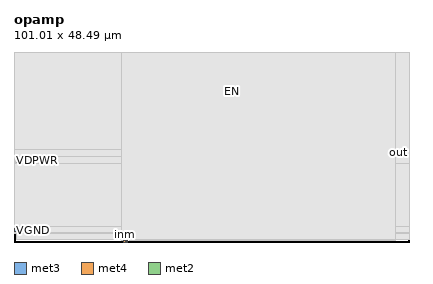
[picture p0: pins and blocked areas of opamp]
MACRO opamp
  CLASS BLOCK ;
  FOREIGN opamp ;
  ORIGIN -78.690 -6.220 ;
  SIZE 101.010 BY 48.490 ;
  PIN VDPWR
    ANTENNAGATEAREA 8.000000 ;
    ANTENNADIFFAREA 205.038895 ;
    PORT
      LAYER met3 ;
        RECT 79.430 26.585 80.430 27.585 ;
    END
  END VDPWR
  PIN inp
    ANTENNAGATEAREA 126.399994 ;
    PORT
      LAYER met4 ;
        RECT 107.350 6.220 107.650 6.520 ;
    END
  END inp
  PIN inm
    ANTENNAGATEAREA 126.399994 ;
    PORT
      LAYER met4 ;
        RECT 106.745 6.220 107.045 6.520 ;
    END
  END inm
  PIN EN
    ANTENNAGATEAREA 0.436500 ;
    PORT
      LAYER met2 ;
        RECT 134.050 44.600 134.350 44.900 ;
    END
  END EN
  PIN VGND
    USE GROUND ;
    PORT
      LAYER met3 ;
        RECT 78.690 8.780 79.255 9.780 ;
    END
  END VGND
  PIN out
    ANTENNADIFFAREA 18.559999 ;
    PORT
      LAYER met3 ;
        RECT 177.595 28.510 178.595 29.510 ;
    END
  END out
  OBS
      LAYER nwell ;
        RECT 79.610 6.770 179.510 54.395 ;
      LAYER li1 ;
        RECT 79.795 6.945 179.330 54.215 ;
      LAYER met1 ;
        RECT 79.605 6.770 179.680 54.365 ;
      LAYER met2 ;
        RECT 79.255 45.180 179.605 54.550 ;
        RECT 79.255 44.320 133.770 45.180 ;
        RECT 134.630 44.320 179.605 45.180 ;
        RECT 79.255 6.830 179.605 44.320 ;
      LAYER met3 ;
        RECT 78.690 29.910 179.700 54.710 ;
        RECT 78.690 28.110 177.195 29.910 ;
        RECT 178.995 28.110 179.700 29.910 ;
        RECT 78.690 27.985 179.700 28.110 ;
        RECT 78.690 26.185 79.030 27.985 ;
        RECT 80.830 26.185 179.700 27.985 ;
        RECT 78.690 10.180 179.700 26.185 ;
        RECT 78.690 9.780 79.255 10.180 ;
        RECT 78.690 8.635 79.255 8.780 ;
        RECT 79.655 8.635 179.700 10.180 ;
        RECT 78.690 8.495 179.700 8.635 ;
        RECT 79.655 8.490 179.700 8.495 ;
      LAYER met4 ;
        RECT 106.165 6.920 175.980 54.650 ;
        RECT 106.165 6.520 106.345 6.920 ;
        RECT 108.050 6.520 175.980 6.920 ;
  END
END opamp
END LIBRARY

